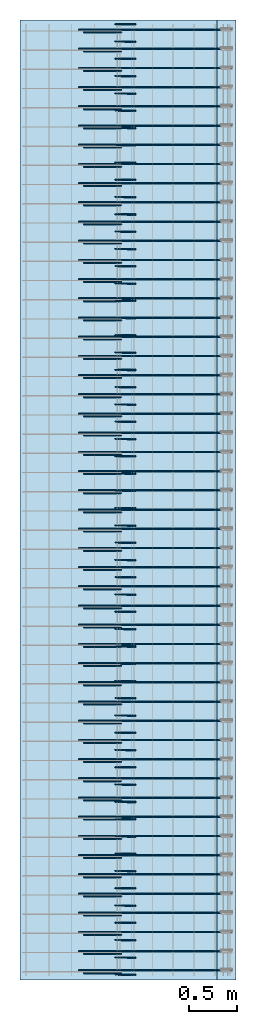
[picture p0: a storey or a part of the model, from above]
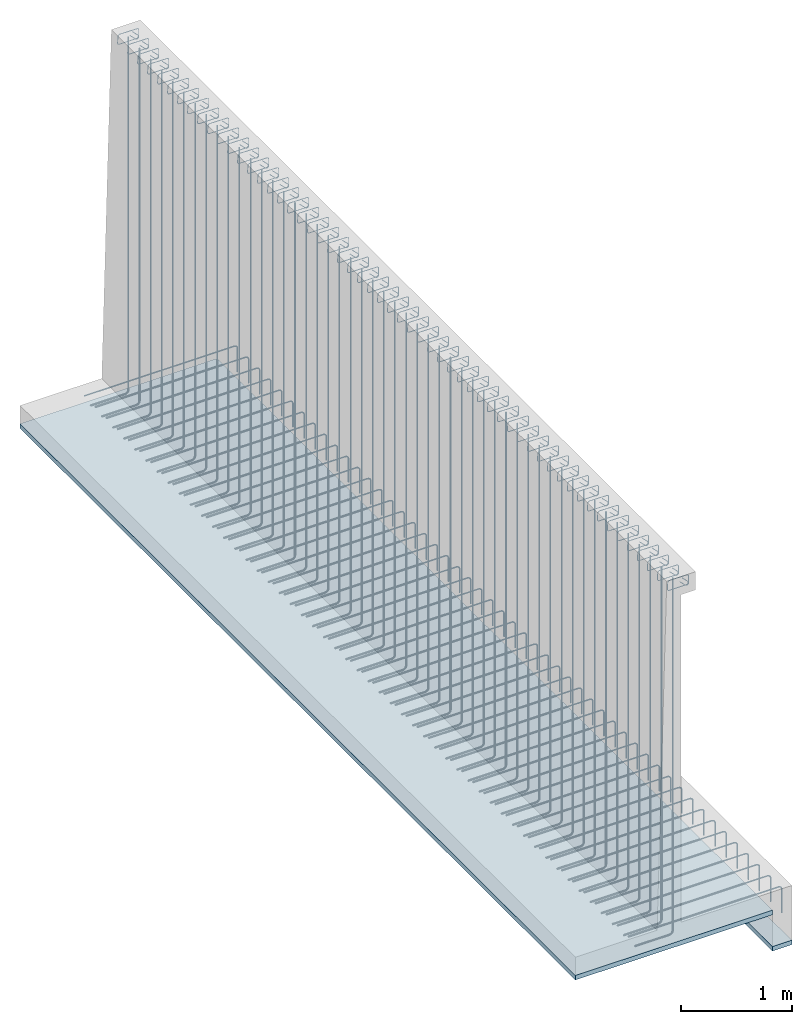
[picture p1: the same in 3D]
Properties of the parts of a building model (IFC2X3)

# File
Description: IFC2x3 Coordination View
File name: D:\Users\Utilisateur\Documents\BIM\Soutènement\mur_de_soutènement.ifc
Time: 2016-04-06T16:41:43
Author: Roger GODIN
Organization: Nemetschek AG, Konrad-Zuse-Platz 1, 81829 Munich / Germany
Written by: The EXPRESS Data Manager Version 5.02.0100.02 : 29 May 2013
Made in: Allplan 2014.1 13.07.2015 - 08:58:29

# IfcAnnotation (2)
In: Leçon 0: Environnement du projet
Name | NOI_UUID
 | e87329bb-fbe1-11e5-83bb-7824afc948f4--4
 | e87329bb-fbe1-11e5-83bb-7824afc948f4--5

# IfcReinforcingBar (9)
In: corrigé
CrossSectionArea: 0.503 m2; Material: haute adhérence
Allplan_ReinforcingBar - Creation flags: 41
Name | NominalDiameter (mm) | Bending diameter | Shape code | Weight per meter | Count of bars/meshes
 | 8 | 16 | B1 | 0.395 | 50 | Allplan_ReinforcingBar - Hook angle - begin: 135; Hook length - begin: 104; Hook bending diameter - begin: 16; Hook angle - end: 135; Hook length - end: 104; Hook bending diameter - end: 16
 | 8 | 16 | B1 | 0.395 | 560 | Allplan_ReinforcingBar - Hook angle - begin: 135; Hook length - begin: 104; Hook bending diameter - begin: 16; Hook angle - end: 135; Hook length - end: 104; Hook bending diameter - end: 16; Delta number of pieces: 504
2 x  | 14 | 28 | A2 | 1.21 | 50
 | 12 | 24 | A1 | 0.888 | 20 | Allplan_ReinforcingBar - Delta number of pieces: 18
 | 12 | 24 | A1 | 0.888 | 30 | Allplan_ReinforcingBar - Delta number of pieces: 18
 | 8 | 16 | A1 | 0.395 | 133 | Allplan_ReinforcingBar - Delta number of pieces: 108
 | 14 | 28 | X1 | 1.21 | 50
 | 8 | 16 | A2 | 0.395 | 50 | Allplan_ReinforcingBar - Hook angle - end: 135; Hook length - end: 52.5664; Hook bending diameter - end: 16

# IfcSlab (2)
In: corrigé
PredefinedType: FLOOR; Material: béton de propreté 50 mm
SlabQuantities - Width: 0.05 m
Allplan Attributes - Unité: m²; Métier: Béton et béton armé; Matériau: béton de propreté
Name | GrossVolume (m3) = NetVolume (m3) | GrossSideArea (m2) | NOI_UUID
 | 0.1 | 2 | 78693026-fbdf-11e5-83bb-7824afc948f4--18
 | 1.025 | 20.5 | 78693026-fbdf-11e5-83bb-7824afc948f4--2
